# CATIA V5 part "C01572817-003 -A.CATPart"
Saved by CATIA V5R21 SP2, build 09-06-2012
Part number: C01572817-003
Revision: ---
Description: PROPRIETARY NOTICE (do not delete / modify)  ***************************************************************************************************  LA SOCIETE EN COMMANDITE  AIRBUS CANADA  ("AIRBUS CANADA")  PAR  L'INTERMEDIAIRE  DE  SES  DIVISIONS  ET/OU  FILIALES  CORPORATIVES,  FOURNIT  LES PRESENTES  INFORMATIONS  AU  GOUVERNEMENT  A  TITRE CONFIDENTIEL. CES  INFORMATIONS ONT UNE TENEUR CONFIDENTIELLE,  AVEC DROITS DE PROPRIETE,  ET NOUS LES CONSIDERONS  EXCLUS  DE   L'APPLICATION  DE  LA LOI SUR L'ACCES A L'INFORMATION  (CANADA),  LES  LOIS  SUR  L'ACCES  A  L'INFORMATION  EUROPEENNES,  LE FREEDOM OF INFORMATION ACT (ETATS-UNIS) ET D'AUTRES LOIS SEMBLABLES. ELLES  PEUVENT  AUSSI  CONSTITUER DES SECRETS INDUSTRIELS DE NOTRE SOCIETE OU DE TIERCES PARTIES. LA DIVULGATION  PUBLIQUE  DE CES  INFORMATIONS NUIRAIT A AIRBUS CANADA OU A DES TIERCES PARTIES.  CES INFORMATIONS PEUVENT EGALEMENT CONTENIR  DES DONNEES QUI SONT CONTROLEE PAR DES LOIS DE CONTROLE DES EXPORTATIONS DU CANADA, L’EUROPE OU LES  ETATS-  UNIS. TOUTE EXPORTATION OU REEXPORTATION DE DONNEES CONTROLEES SANS AUTORISATION EST STRICTEMENT INTERDITE.  TOUTE INTENTION DE LES DIVULGUER EN TOUT OU EN PARTIE DEVRA ETRE SIGNIFIEE A L'AVANCE ET PAR ECRIT AU VICE-  PRESIDENT, SERVICES JURIDIQUES ET CONFORMITE ET SECRETAIRE CORPORATIF D'AIRBUS CANADA.    AIRBUS CANADA LIMITED PARTNERSHIP  ("AIRBUS CANADA"),  BY ITS AFFILIATES AND/OR SUBSIDIARIES, PROVIDES THIS  INFORMATION TO THE GOVERNMENT IN CONFIDENCE. THIS IS PROPRIETARY CONFIDENTIAL INFORMATION WHICH WE CONSIDER  EXCLUDED  FROM  THE  APPLICATION OF THE ACCESS TO INFORMATION ACT (CANADA),  THE FREEDOM OF INFORMATION ACT  (U.S.A.),  THE ACCESS TO INFORMATION LAWS IN EUROPE, AND OTHER SIMILAR LEGISLATION. AND MAY ALSO CONSTITUTE  TRADE SECRETS OF OUR  COMPANY OR THIRD PARTIES.  PUBLIC  RELEASE  OF  THIS INFORMATION  WOULD BE HARMFUL TO  AIRBUS CANADA OR THIRD PARTIES.  THIS  INFORMATION  MAY  ALSO  CONTAIN DATA THAT IS CONTROLLED BY CANADIAN,  EUROPEAN, OR U.S.A. EXPORT CONTROL LAWS. ANY UNAUTHORIZED EXPORT OR RE-EXPORT OF ANY EXPORT CONTROLLED DATA  IS STRICTLY PROHIBITED  ANY INTENTION TO DISCLOSE SUCH INFORMATION,  OR  PART THEREOF,  MUST BE NOTIFIED IN  ADVANCE AND IN WRITING TO THE VICE PRESIDENT, LEGAL AND COMPLIANCE AND CORPORATE SECRETARY OF AIRBUS CANADA.        LES RENSEIGNEMENTS,  LES DONNEES  ET  DESSINS  TECHNIQUES  DIVULGUES  DANS  LES PRESENTES SONT LA PROPRIETE  EXCLUSIVE DE LA SOCIETE EN COMMANDITE AIRBUS CANADA ("AIRBUS CANADA") OU COMPORTENT DES DROITS DE PROPRIETE  APPARTENANT  A  AUTRUI ET NE PEUVENT ETRE DIVULGUES  A  QUICONQUE  NI  UTILISES PAR QUI QUE CE SOIT SANS LE  CONSENTEMENT  ECRIT  D’AIRBUS  CANADA.  LE DETENTEUR DES  PRESENTES  S'ENGAGE, DANS TOUTES CIRCONSTANCES, A  GARDER CONFIDENTIELS LES DONNEES ET DESSINS TECHNIQUES QU'ELLES CONTIENNENT.   CE QUI PRECEDE NE S'APPLIQUE  PAS  AUX PERSONNES  QUI  ONT DES DROITS DE PROPRIETE SUR CES RENSEIGNEMENTS,  DONNEES TECHNIQUES ET DESSINS  DANS LA MESURE OU CES DROITS EXISTENT.    THE INFORMATION,  TECHNICAL DATA  AND  DESIGNS DISCLOSED HEREIN ARE THE EXCLUSIVE PROPERTY OF AIRBUS CANADA  LIMITED PARTNERSHIP  ("AIRBUS CANADA")  OR  CONTAIN PROPRIETARY RIGHTS OF OTHERS  AND ARE NOT TO BE USED OR  DISCLOSED  TO  OTHERS WITHOUT THE WRITTEN CONSENT OF AIRBUS CANADA.  THE RECIPIENT OF THIS DOCUMENT, BY ITS  RETENTION  AND  USE  AGREES TO  HOLD  IN  CONFIDENCE  THE  TECHNICAL DATA AND DESIGNS CONTAINED HEREIN. THE  FOREGOING SHALL NOT APPLY TO PERSONS HAVING PROPRIETARY RIGHTS TO SUCH INFORMATION,  TECHNICAL DATA OR SUCH  DESIGNS TO THE EXTENT THAT SUCH RIGHTS EXIST.    Copyright 2020 Airbus Canada Limited Partnership. All Rights Reserved.  ***********************************
Property "Title": "AXLE, ROLLER, SLIDE, OWE"
Property "Dataset Type": "DETAIL"
Property "Supplier Name And CAGE Code": "AIRBUS CANADA LIMITED PARTNERSHIP L0J48"
Property "Major Supplier Code": "LP"
Property "3D Only": "Y"
Property "Material Form": "BAR - ROUND"
Property "Finish Code": "S010"
Property "PCCN": "2"
Property "Organization": "DESIGN"
Property "Dimensions": "DIMENSIONS ARE IN INCHES"
Property "Roughness": "ALL MACHINED SURFACES 125 Ra MAX"
Property "Eng. Tolerances": "LINEAR .XX= +/-.03; .XXX= +/-.010; ANGULAR= +/-0.5 DEG"
Property "Tool Design Tolerances": "LINEAR .X= +/-.06; .XX= +/-.015; .XXX= +/-.005; .XXXX= +/-.001; ANGULAR= +/-0.5 DEG"
Property "Design Authority Program": "BD-500"
Property "Color Coded": "N"
Property "Thickness": 0
Property "Inside Diameter": 0
Property "Outside Diameter": 1
Property "Length": 0
Property "Width": 0
Property "Wall": 0
Property "Wire Gauge": "-"
Property "Alloy": "15-5PH"
Property "Final Condition": "H1025"
Property "Density": "N/A"
Property "Form": "N/A"
Property "Grade/Composition": "N/A"
Property "Material Class": "N/A"
Property "Mesh Cell Size": "-"
Property "Standard Spec Die": "-"
Property "Type": "N/A"
Property "Style": "N/A"
Property "MFG Process": "MACHINED"
Property "Material Specification Production": "AMS5659"
Property "Material Description Production": "CRES"
Property "Project": "BA"
Publications: "Extract_Datum_A", "PartBody", "Extract_Datum_B"
Material "ST-15-5PH-B": density 7833.41 kg/m3, Young's modulus 1.9719e+11 Pa, Poisson ratio 0.27
Bounding box of the stored display mesh (mm): x -29.718 to 0.508, y -5.579 to 13.835, z -5.588 to 15.095
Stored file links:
  C:\Users\CQQZ006\Desktop\A220钢钛件\舱门\C01572817-003\C01572817-003 -A.CATPart

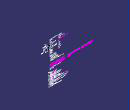
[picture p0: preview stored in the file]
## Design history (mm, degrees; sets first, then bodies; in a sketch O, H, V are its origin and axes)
AxisSystem1 "Absolute Axis System": origin (0, 0, 0), X (1, 0, 0), Y (0, 1, 0), Z (0, 0, 1)
Part_3D_Annotations1 "CATTPSSet"
Set1 "Pilot_Holes"
  Set2 "1/8"
    Point1: type Center, Curve edge [face of Pad1 from Sketch2.A8 | start face of Pocket1]
    Point2: type Center, Curve edge [face of Pad1 from Sketch2.A7 | start face of Pocket1]
    Line1: type PtDir, RefPoint Point1, Direction start face of Pocket1, Start -6.35, End 6.35
    Line2: type Normal, RefPoint Point2, RefSkin start face of Pocket1, Start -6.35, End 6.35
Set3 "Geometrical Set for 3D Annotations"
  Set4 "No Show Geometry"
    Extract1 "Extract_Datum_A": ExtractElem face of Pocket1 from Sketch3.A1
    Extract2 "Extract_Datum_B": ExtractElem start face of Pocket1
  Set5 "VIEW B"
    Point3: (0, 0, 0), relative to Sketch1, in AxisSystem1
Set6 "Construction_Geometry"
  Set7 "Sketches_Not_Used_By_PartBody"
    Sketch1 on Plane3, origin (-24.13, 0, 0), H (0, 1, 0), V (0, 0, 1)
      point P1 (12.954, 2.0107)
      reference projected arc E1 centre (8.7587, 4.8752) radius 5.08 from (9.1481, -0.1898) to (8.9371, 9.9521) ccw from Sketch2.A8
      reference intersected line E2 through (0, 0) direction (0, 1) from zx-plane
      distance E2 P1 = 12.954
      coincidence: E1 P1
  Plane1: type Offset, RefPlane yz-plane, Offset 23.368, reversed
  Plane2: type Offset, RefPlane Plane1, Offset 1.524, reversed
  Plane3: type Offset, RefPlane yz-plane, Offset 24.13, reversed
Body1 (main body)
  Sketch2 on Plane2, origin (-24.892, 0, 0), H (0, 1, 0), V (0, 0, 1)
    arc A1 centre (0, 0) radius 5.588 from (-4.8458, 2.7828) to (4.7883, -2.8807) ccw
    construction circle A2 centre (0, 0) radius 3.1661
    construction circle A3 centre (0, 0) radius 3.6741
    construction circle A4 centre (0, 0) radius 10.0241
    construction arc A5 centre (0, 0) radius 15.1041 from (13.1974, 7.3459) to (0, 15.1041) ccw
    construction line L1 (0, 0) -> (0, 10.0241)
    point P1 (0, 10.0241)
    construction circle A6 centre (0, 10.0241) radius 10.16
    point P2 (8.7587, 4.8752)
    construction line L2 (0, 0) -> (8.7587, 4.8752)
    arc A7 centre (0, 10.0241) radius 5.08 from (4.3492, 12.6491) to (-4.6151, 7.901) ccw
    arc A8 centre (8.7587, 4.8752) radius 5.08 from (9.1481, -0.1898) to (8.9371, 9.9521) ccw
    point P3 (13.1974, 7.3459)
    point P4 (0, 15.1041)
    construction line L3 (-5.0735, 10.2816) -> (-5.5808, 0.2832)
    construction line L4 (2.9617, -4.7386) -> (11.4511, 0.5674)
    point P5 (11.4511, 0.5674)
    point P6 (2.9617, -4.7386)
    point P7 (-5.5808, 0.2832)
    point P8 (-5.0735, 10.2816)
    construction line L5 (2.5744, 14.4035) -> (11.3331, 9.2546)
    point P9 (2.5744, 14.4035)
    point P10 (11.3331, 9.2546)
    arc A9 centre (9.5765, -5.7614) radius 5.588 from (9.1481, -0.1898) to (4.7883, -2.8807) ccw
    arc A10 centre (9.1333, 15.5367) radius 5.588 from (8.9371, 9.9521) to (4.3492, 12.6491) cw
    arc A11 centre (-9.6916, 5.5656) radius 5.588 from (-4.8458, 2.7828) to (-4.6151, 7.901) ccw
    radius A1 = 5.588
    radius A2 = 3.1661
    distance A3 A2 = 0.508
    distance A4 A3 = 6.35
    distance A5 A4 = 5.08
    radius A6 = 10.16
    radius A9 = 5.588
    radius A10 = 5.588
    radius A11 = 5.588
    coincidence: P1 A4, A6 P2, P2 A4, L1 V, P4 A7, P3 A8, A8 P5, A1 P6, A8 P10, A7 P9, A1 P7, A7 P8
    tangency: A7 A5, A8 A5, L3 A7, L3 A1, L4 A1, L4 A8, L5 A8, L5 A7, A9 A8, A9 A1, A10 A8, A10 A7, A11 A1, A11 A7
  Pad1: profile Sketch2, direction (1, 0, 0), up to yz-plane, offset 0.508
  Body2
    Sketch3 on Plane1, origin (-23.368, 0, 0), H (0, 1, 0), V (0, 0, 1)
      circle A1 centre (0, 0) radius 3.1661
      circle A2 centre (0, 0) radius 17.78
      radius A1 = 3.1661
      radius A2 = 17.78
    Pocket1: profile Sketch3, direction (1, 0, 0), up to yz-plane, offset 0.508
    Fillet1: radius 0.381, on edge [face of Pocket1 from Sketch3.A1 | start face of Pocket1]
  Assemble1: tool Body2
  Sketch4 on start face of Pocket1, origin (-23.368, 0, 10.0241), H (0, 1, 0), V (0, 0, 1)
    point P1 (0, 0)
    intersected point E1 (0, 0) from Line2
    coincidence: E1 P1
  Hole1: placed by Sketch4, at (-23.368, 0, 10.0241) direction (-1, 0, 0), diameter 2.1, through (limit type 6)
  Sketch5 on start face of Pocket1, origin (-23.368, 8.7587, 4.8752), H (0, 1, 0), V (0, 0, 1)
    point P1 (0, 0)
    intersected point E1 (0, 0) from Line1
    coincidence: E1 P1
  Hole2: placed by Sketch5, at (-23.368, 8.7587, 4.8752) direction (-1, 0, 0), diameter 2.1, through (limit type 6)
